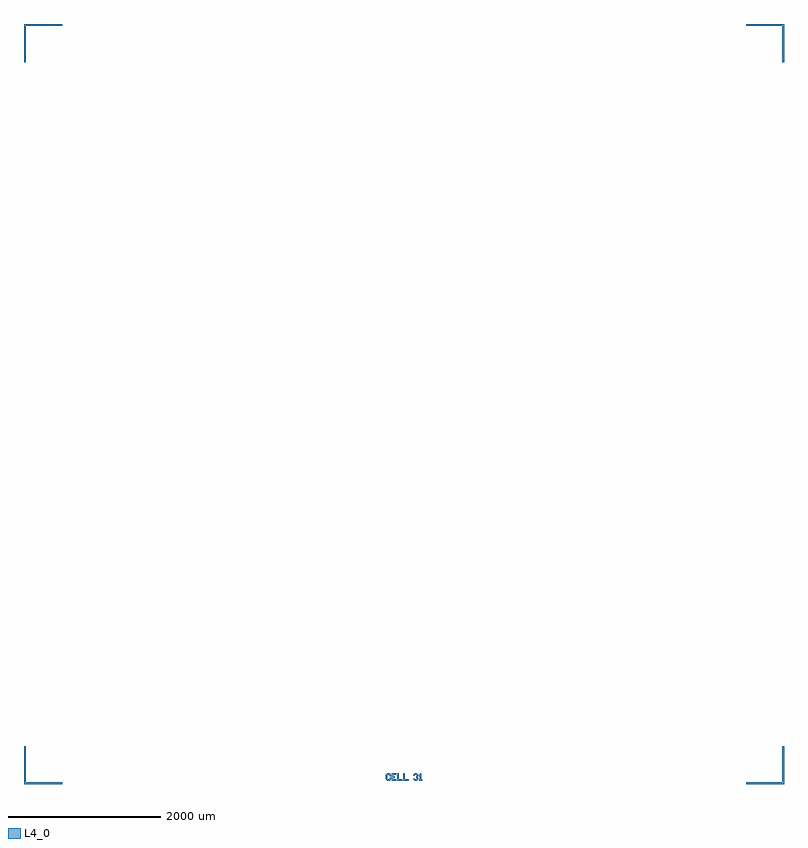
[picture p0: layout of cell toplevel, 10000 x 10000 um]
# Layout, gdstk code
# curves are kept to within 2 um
import gdstk
lib = gdstk.Library(unit=1e-6, precision=1e-09)
def P(c, l, *ps):  # polygons
    for p in ps: c.add(gdstk.Polygon(p, *l))
L4_0 = (4, 0)

toplevel = lib.new_cell('toplevel')
P(toplevel, L4_0, [(5000,5000),(5000,4500),(4980,4500),(4980,4980),(4500,4980),(4500,5000)],
  [(-5000,5000),(-5000,4500),(-4980,4500),(-4980,4980),(-4500,4980),(-4500,5000)],
  [(5000,-5000),(5000,-4500),(4980,-4500),(4980,-4980),(4500,-4980),(4500,-5000)],
  [(-5000,-5000),(-5000,-4500),(-4980,-4500),(-4980,-4980),(-4500,-4980),(-4500,-5000)],
  [(-220,-4960),(-240,-4940),(-240,-4880),(-220,-4860),(-190,-4860),(-170,-4880),(-170,-4900),(-190,-4900),(-190,-4890),(-200,-4880),(-210,-4880),(-220,-4890),(-220,-4930),(-210,-4940),(-200,-4940),(-190,-4930),(-190,-4920),(-170,-4920),(-170,-4940),(-190,-4960)],
  [(-100,-4860),(-100,-4880),(-140,-4880),(-140,-4900),(-120,-4900),(-120,-4920),(-140,-4920),(-140,-4940),(-100,-4940),(-100,-4960),(-160,-4960),(-160,-4860),(-100,-4860)],
  [(-90,-4860),(-70,-4860),(-70,-4940),(-20,-4940),(-20,-4960),(-90,-4960),(-90,-4860)],
  [(-10,-4860),(10,-4860),(10,-4940),(60,-4940),(60,-4960),(-10,-4960),(-10,-4860)],
  [(170,-4860),(190,-4880),(190,-4900),(180,-4910),(190,-4920),(190,-4940),(170,-4960),(140,-4960),(120,-4940),(120,-4930),(140,-4930),(150,-4940),(160,-4940),(170,-4930),(160,-4920),(160,-4900),(170,-4890),(160,-4880),(150,-4880),(140,-4890),(120,-4890),(120,-4880),(140,-4860)],
  [(210,-4900),(200,-4900),(200,-4880),(220,-4860),(230,-4860),(230,-4940),(240,-4940),(240,-4960),(200,-4960),(200,-4940),(210,-4940)])

lib.write_gds('toplevel.gds')
